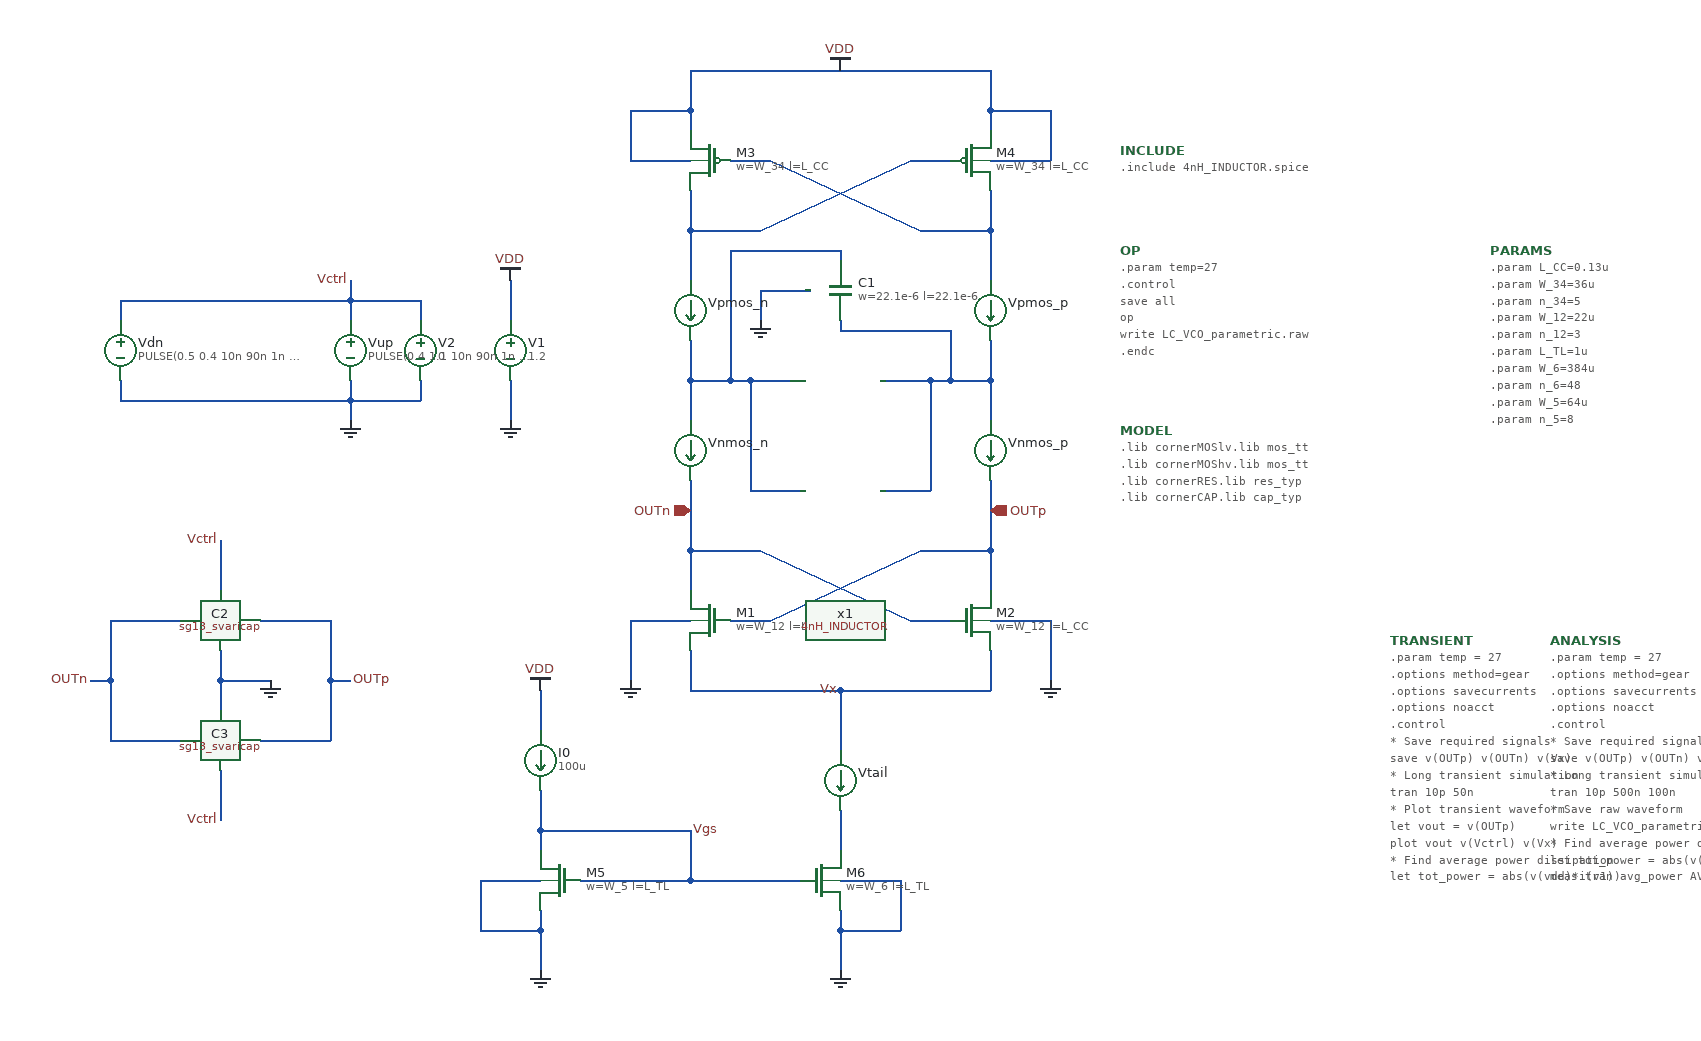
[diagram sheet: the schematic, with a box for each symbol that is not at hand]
v {xschem version=3.4.6 file_version=1.2}
G {}
K {}
V {}
S {}
E {}
N 2320 70 2320 110 {
lab=#net1}
N 2060 40 2100 40 {
lab=#net1}
N 2250 110 2320 110 {
lab=#net1}
N 2020 -50 2320 -50 {
lab=VDD}
N 2280 260 2320 260 {lab=#net2}
N 2080 260 2120 260 {lab=#net3}
N 2020 260 2060 260 {lab=#net3}
N 2260 260 2280 260 {lab=#net2}
N 2020 -10 2020 10 {lab=VDD}
N 2320 -10 2320 10 {lab=VDD}
N 2320 40 2380 40 {lab=VDD}
N 2380 -10 2380 40 {lab=VDD}
N 1960 40 2020 40 {lab=VDD}
N 1960 -10 1960 40 {lab=VDD}
N 1960 -10 2020 -10 {lab=VDD}
N 2380 500 2380 560 {lab=GND}
N 2320 500 2380 500 {lab=GND}
N 2320 530 2320 570 {
lab=Vx}
N 1960 500 1960 560 {lab=GND}
N 1960 500 2020 500 {lab=GND}
N 2020 530 2020 570 {
lab=Vx}
N 2320 430 2320 480 {
lab=OUTp}
N 2020 430 2020 480 {
lab=OUTn}
N 2020 -50 2020 -10 {lab=VDD}
N 2320 -50 2320 -10 {lab=VDD}
N 2240 40 2280 40 {
lab=#net4}
N 2060 500 2100 500 {
lab=OUTp}
N 2240 500 2280 500 {
lab=OUTn}
N 2020 110 2090 110 {
lab=#net4}
N 2020 70 2020 110 {
lab=#net4}
N 2090 110 2240 40 {lab=#net4}
N 2100 40 2250 110 {lab=#net1}
N 2020 430 2090 430 {
lab=OUTn}
N 2250 430 2320 430 {
lab=OUTp}
N 2100 500 2250 430 {lab=OUTp}
N 2090 430 2240 500 {lab=OUTn}
N 2320 -10 2380 -10 {lab=VDD}
N 2170 810 2230 810 {lab=GND}
N 2230 760 2230 810 {lab=GND}
N 2170 760 2230 760 {lab=GND}
N 2170 810 2170 850 {lab=GND}
N 2170 790 2170 810 {lab=GND}
N 2170 570 2320 570 {
lab=Vx}
N 1840 260 1840 300 {lab=GND}
N 2320 220 2320 260 {lab=#net2}
N 2320 110 2320 160 {lab=#net1}
N 2320 260 2320 300 {lab=#net2}
N 2320 360 2320 430 {lab=OUTp}
N 2170 570 2170 630 {lab=Vx}
N 2020 570 2170 570 {
lab=Vx}
N 2170 690 2170 730 {lab=#net5}
N 1810 810 1870 810 {lab=GND}
N 1810 760 1810 810 {lab=GND}
N 1810 760 1870 760 {lab=GND}
N 1870 810 1870 850 {lab=GND}
N 1870 790 1870 810 {lab=GND}
N 2020 760 2130 760 {lab=Vgs}
N 1870 710 1870 730 {lab=Vgs}
N 2020 710 2020 760 {lab=Vgs}
N 1910 760 2020 760 {lab=Vgs}
N 1870 710 2020 710 {lab=Vgs}
N 1870 670 1870 710 {lab=Vgs}
N 1870 570 1870 610 {lab=VDD}
N 2020 220 2020 260 {lab=#net3}
N 2020 110 2020 160 {lab=#net4}
N 2020 360 2020 430 {lab=OUTn}
N 2020 260 2020 300 {lab=#net3}
N 2170 210 2280 210 {lab=#net2}
N 2060 130 2170 130 {lab=#net3}
N 2170 200 2170 210 {lab=#net2}
N 2280 210 2280 260 {lab=#net2}
N 2060 130 2060 260 {lab=#net3}
N 2170 130 2170 140 {lab=#net3}
N 2080 370 2130 370 {lab=#net3}
N 2080 260 2080 370 {lab=#net3}
N 2060 260 2080 260 {lab=#net3}
N 2210 370 2260 370 {lab=#net2}
N 2260 260 2260 370 {lab=#net2}
N 2210 260 2260 260 {lab=#net2}
N 1680 280 1680 300 {lab=GND}
N 1680 180 1680 200 {lab=Vctrl}
N 2090 170 2090 200 {lab=GND}
N 2090 170 2140 170 {lab=GND}
N 1680 180 1750 180 {lab=Vctrl}
N 1750 180 1750 200 {lab=Vctrl}
N 1750 260 1750 280 {lab=GND}
N 1680 280 1750 280 {lab=GND}
N 1680 260 1680 280 {lab=GND}
N 1680 160 1680 180 {lab=Vctrl}
N 1840 160 1840 200 {lab=VDD}
N 1450 180 1450 200 {lab=Vctrl}
N 1450 180 1680 180 {lab=Vctrl}
N 1450 280 1680 280 {lab=GND}
N 1450 260 1450 280 {lab=GND}
N 1550 560 1550 590 {lab=GND}
N 1550 560 1600 560 {lab=GND}
N 1550 530 1550 560 {lab=GND}
N 1440 620 1510 620 {lab=OUTn}
N 1440 560 1440 620 {lab=OUTn}
N 1440 500 1510 500 {lab=OUTn}
N 1590 620 1660 620 {lab=OUTp}
N 1660 560 1660 620 {lab=OUTp}
N 1590 500 1660 500 {lab=OUTp}
N 1660 560 1680 560 {lab=OUTp}
N 1660 500 1660 560 {lab=OUTp}
N 1420 560 1440 560 {lab=OUTn}
N 1440 500 1440 560 {lab=OUTn}
N 1550 420 1550 470 {lab=Vctrl}
N 1550 650 1550 700 {lab=Vctrl}
C {opin.sym} 2320 390 0 0 {name=p11 lab=OUTp
}
C {opin.sym} 2020 390 0 1 {name=p12 lab=OUTn


}
C {devices/vdd.sym} 2170 -50 0 0 {name=l7 lab=VDD}
C {sg13g2_pr/sg13_lv_nmos.sym} 2150 760 0 0 {name=M6
l=L_TL
w=W_6
ng=n_6
m=1
model=sg13_lv_nmos
spiceprefix=X
}
C {sg13g2_pr/sg13_lv_pmos.sym} 2300 40 0 0 {name=M4
l=L_CC
w=W_34
ng=n_34
m=1
model=sg13_lv_pmos
spiceprefix=X
}
C {sg13g2_pr/sg13_lv_pmos.sym} 2040 40 0 1 {name=M3
l=L_CC
w=W_34
ng=n_34
m=1
model=sg13_lv_pmos
spiceprefix=X5}
C {sg13g2_pr/sg13_lv_nmos.sym} 2300 500 0 0 {name=M2
l=L_CC
w=W_12
ng=n_12
m=1
model=sg13_lv_nmos
spiceprefix=X
}
C {sg13g2_pr/sg13_lv_nmos.sym} 2040 500 0 1 {name=M1
l=L_CC
w=W_12
ng=n_12
m=1
model=sg13_lv_nmos
spiceprefix=X
}
C {gnd.sym} 1960 560 0 0 {name=l1 lab=GND}
C {gnd.sym} 2380 560 0 0 {name=l2 lab=GND}
C {gnd.sym} 2170 850 0 0 {name=l3 lab=GND}
C {devices/code_shown.sym} 2450 130 0 0 {name=OP only_toplevel=true 
value="
.param temp=27
.control
save all 
op
write LC_VCO_parametric.raw
.endc
"}
C {vsource.sym} 1840 230 0 0 {name=V1 value=1.2 savecurrent=false}
C {gnd.sym} 1840 300 0 0 {name=l4 lab=GND}
C {devices/vdd.sym} 1840 160 0 0 {name=l5 lab=VDD}
C {devices/code_shown.sym} 2450 310 0 0 {name=MODEL only_toplevel=true
format="tcleval( @value )"
value="
.lib cornerMOSlv.lib mos_tt
.lib cornerMOShv.lib mos_tt
.lib cornerRES.lib res_typ
.lib cornerCAP.lib cap_typ
"}
C {devices/launcher.sym} 2510 450 0 0 {name=h1
descr="OP annotate" 
tclcommand="xschem annotate_op"
}
C {ammeter.sym} 2320 190 0 0 {name=Vpmos_p savecurrent=true spice_ignore=0}
C {ammeter.sym} 2320 330 0 0 {name=Vnmos_p savecurrent=true spice_ignore=0}
C {ammeter.sym} 2170 660 0 0 {name=Vtail savecurrent=true spice_ignore=0}
C {lab_pin.sym} 2170 570 1 0 {name=p2 sig_type=std_logic lab=Vx
}
C {devices/code_shown.sym} 2820 130 0 0 {name=PARAMS only_toplevel=true 
value="
.param L_CC=0.13u

.param W_34=36u
.param n_34=5

.param W_12=22u
.param n_12=3

.param L_TL=1u

.param W_6=384u
.param n_6=48

.param W_5=64u
.param n_5=8
"}
C {sg13g2_pr/sg13_lv_nmos.sym} 1890 760 0 1 {name=M5
l=L_TL
w=W_5
ng=n_5
m=1
model=sg13_lv_nmos
spiceprefix=X
}
C {gnd.sym} 1870 850 0 1 {name=l8 lab=GND}
C {isource.sym} 1870 640 0 1 {name=I0 value=100u}
C {devices/vdd.sym} 1870 570 0 0 {name=l9 lab=VDD}
C {ammeter.sym} 2020 190 0 1 {name=Vpmos_n savecurrent=true spice_ignore=0}
C {ammeter.sym} 2020 330 0 1 {name=Vnmos_n savecurrent=true spice_ignore=0}
C {lab_pin.sym} 2020 710 2 0 {name=p1 sig_type=std_logic lab=Vgs
}
C {devices/code_shown.sym} 2450 30 0 0 {name=INCLUDE only_toplevel=true
format="tcleval( @value )"
value="
.include 4nH_INDUCTOR.spice
"}
C {simulator_commands.sym} 2880 520 0 0 {name=ANALYSIS only_toplevel=true 
value="
.param temp = 27
.options method=gear
.options savecurrents
.options noacct

.control

* Save required signals
save v(OUTp) v(OUTn) v(Vx)

* Long transient simulation
tran 10p 500n 100n

* Save raw waveform
write LC_VCO_parametric_tb.raw

* Find average power dissipation
let tot_power = abs(v(vdd)*i(v1))
meas tran avg_power AVG tot_power FROM=400n TO=450n

* Plot steady-state waveform
let vout = v(OUTp)
meas tran vout_pp PP vout FROM=400n TO=450n
plot vout xlimit 400n 405n

* FFT analysis
setplot tran1
linearize vout
set specwindow=blackman
fft vout

* Plot FFT spectrum
let power_db = db(vout)
plot power_db xlimit 2.34G 2.54G ylimit -200 0

* Find the maximum magnitude value between 2G and 3G
meas sp max_power_db max power_db FROM=2G TO=3G

* Save FFT data
wrdata fft_output_parametric.txt frequency power_db

* Save waveform for external processing
wrdata vco_waveform_parametric.txt power_db

.endc
"
}
C {vsource.sym} 1680 230 0 1 {name=Vup value="PULSE(0.4 1.1 10n 90n 1n 1s 2s)" savecurrent=false
}
C {gnd.sym} 1680 300 0 0 {name=l6 lab=GND}
C {lab_pin.sym} 1680 160 1 0 {name=p4 sig_type=std_logic lab=Vctrl
}
C {sg13g2_pr/cap_rfcmim.sym} 2170 170 0 0 {name=C1 
model=cap_rfcmim
lvs_model=rfcmim
w=22.1e-6
l=22.1e-6
wfeed=10.0e-6
spiceprefix=X}
C {gnd.sym} 2090 200 0 0 {name=l11 lab=GND}
C {vsource.sym} 1750 230 0 0 {name=V2 value=0 savecurrent=false
spice_ignore=true}
C {vsource.sym} 1450 230 0 1 {name=Vdn value="PULSE(0.5 0.4 10n 90n 1n 1s 2s)" savecurrent=false
spice_ignore=true}
C {sg13g2_pr/sg13_svaricap.sym} 1550 620 2 0 {name=C3 
model=sg13_hv_svaricap 
w=9.74u 
l=0.8u 
Nx=7
spiceprefix=X
}
C {sg13g2_pr/sg13_svaricap.sym} 1550 500 0 1 {name=C2 
model=sg13_hv_svaricap 
w=9.74u 
l=0.8u 
Nx=7
spiceprefix=X
}
C {lab_pin.sym} 1550 420 1 0 {name=p3 sig_type=std_logic lab=Vctrl
}
C {gnd.sym} 1600 560 3 0 {name=l10 lab=GND}
C {lab_pin.sym} 1680 560 2 0 {name=p6 sig_type=std_logic lab=OUTp
}
C {lab_pin.sym} 1420 560 2 1 {name=p7 sig_type=std_logic lab=OUTn
}
C {lab_pin.sym} 1550 700 3 0 {name=p5 sig_type=std_logic lab=Vctrl
}
C {simulator_commands.sym} 2720 520 0 0 {name=TRANSIENT only_toplevel=true 
value="
.param temp = 27
.options method=gear
.options savecurrents
.options noacct

.control

* Save required signals
save v(OUTp) v(OUTn) v(Vx)

* Long transient simulation
tran 10p 50n

* Plot transient waveform
let vout = v(OUTp)
plot vout v(Vctrl) v(Vx)

* Find average power dissipation
let tot_power = abs(v(vdd)*i(v1))
plot tot_power xlimit 20n 35n

.endc
"}
C {/home/designer/shared/LC_VCO_FPLL/xschem/4nH_INDUCTOR.sym} 2170 380 0 0 {name=x1}
